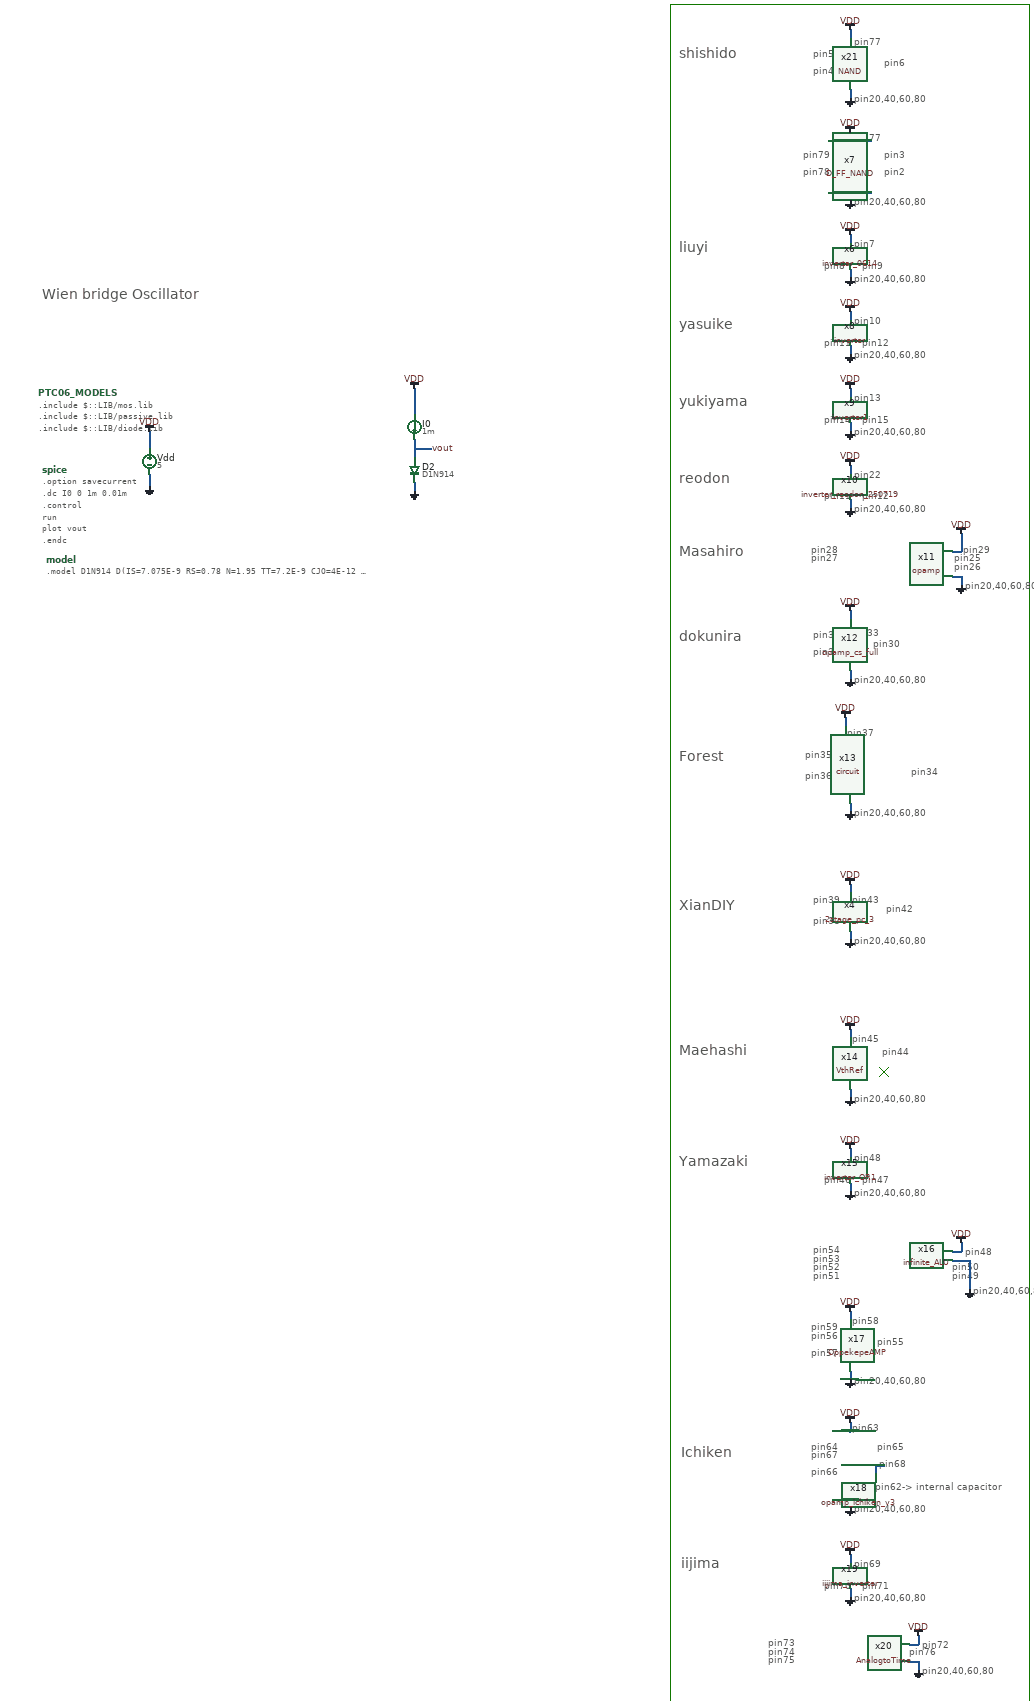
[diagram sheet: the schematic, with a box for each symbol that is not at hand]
v {xschem version=3.4.8RC file_version=1.3}
G {}
K {}
V {}
S {}
F {}
E {}
L 4 1090 1410 1110 1430 {}
L 4 1090 1430 1110 1410 {}
L 4 600 -1080 600 2900 {}
L 4 1440 -1080 1440 2900 {}
L 4 600 -1080 1440 -1080 {}
L 4 600 2900 1440 2900 {}
T {pin8} 960 -480 0 0 0.2 0.2 {}
T {pin9} 1050 -480 0 0 0.2 0.2 {}
T {pin79} 910 -740 0 0 0.2 0.2 {}
T {pin78} 910 -700 0 0 0.2 0.2 {}
T {pin77} 1030 -780 0 0 0.2 0.2 {}
T {pin3} 1100 -740 0 0 0.2 0.2 {}
T {pin2} 1100 -700 0 0 0.2 0.2 {}
T {liuyi} 620 -520 0 0 1 1 {}
T {pin20,40,60,80} 1030 -630 0 0 0.2 0.2 {}
T {pin20,40,60,80} 1030 -450 0 0 0.2 0.2 {}
T {pin7} 1030 -530 0 0 0.2 0.2 {}
T {shishido} 620 -975 0 0 1 1 {}
T {pin20,40,60,80} 1030 -270 0 0 0.2 0.2 {}
T {pin11} 960 -300 0 0 0.2 0.2 {}
T {yasuike} 620 -340 0 0 1 1 {}
T {pin12} 1050 -300 0 0 0.2 0.2 {}
T {pin10} 1030 -350 0 0 0.2 0.2 {}
T {pin20,40,60,80} 1030 -90 0 0 0.2 0.2 {}
T {pin14} 960 -120 0 0 0.2 0.2 {}
T {pin15} 1050 -120 0 0 0.2 0.2 {}
T {pin13} 1030 -170 0 0 0.2 0.2 {}
T {yukiyama} 620 -160 0 0 1 1 {}
T {pin20,40,60,80} 1030 90 0 0 0.2 0.2 {}
T {pin11} 960 60 0 0 0.2 0.2 {}
T {pin12} 1050 60 0 0 0.2 0.2 {}
T {pin22} 1030 10 0 0 0.2 0.2 {}
T {reodon} 620 20 0 0 1 1 {}
T {Masahiro} 620 190 0 0 1 1 {}
T {pin25} 1265 205 0 0 0.2 0.2 {}
T {pin20,40,60,80} 1290 270 0 0 0.2 0.2 {}
T {pin29} 1285 185 0 0 0.2 0.2 {}
T {pin26} 1265 225 0 0 0.2 0.2 {}
T {pin27} 930 205 0 0 0.2 0.2 {}
T {pin28} 930 185 0 0 0.2 0.2 {}
T {pin20,40,60,80} 1030 490 0 0 0.2 0.2 {}
T {pin31} 935 385 0 0 0.2 0.2 {}
T {pin32} 935 425 0 0 0.2 0.2 {}
T {pin30} 1075 405 0 0 0.2 0.2 {}
T {pin33} 1025 380 0 0 0.2 0.2 {}
T {dokunira} 620 390 0 0 1 1 {}
T {Forest} 620 670 0 0 1 1 {}
T {pin20,40,60,80} 1030 800 0 0 0.2 0.2 {}
T {Maehashi} 620 1360 0 0 1 1 {}
T {pin20,40,60,80} 1030 1470 0 0 0.2 0.2 {}
T {pin45} 1025 1330 0 0 0.2 0.2 {}
T {pin44} 1095 1360 0 0 0.2 0.2 {}
T {pin20,40,60,80} 1030 1690 0 0 0.2 0.2 {}
T {pin46} 960 1660 0 0 0.2 0.2 {}
T {pin47} 1050 1660 0 0 0.2 0.2 {}
T {pin48} 1030 1610 0 0 0.2 0.2 {}
T {Yamazaki} 620 1620 0 0 1 1 {}
T {pin20,40,60,80} 1310 1920 0 0 0.2 0.2 {}
T {pin48} 1290 1830 0 0 0.2 0.2 {}
T {pin50} 1260 1865 0 0 0.2 0.2 {}
T {pin49} 1260 1885 0 0 0.2 0.2 {}
T {pin54} 935 1825 0 0 0.2 0.2 {}
T {pin53} 935 1845 0 0 0.2 0.2 {}
T {pin52} 935 1865 0 0 0.2 0.2 {}
T {pin51} 935 1885 0 0 0.2 0.2 {}
T {pin20,40,60,80} 1030 2130 0 0 0.2 0.2 {}
T {pin59} 930 2005 0 0 0.2 0.2 {}
T {pin58} 1025 1990 0 0 0.2 0.2 {}
T {pin55} 1085 2040 0 0 0.2 0.2 {}
T {pin57} 930 2065 0 0 0.2 0.2 {}
T {pin56} 930 2025 0 0 0.2 0.2 {}
T {pin20,40,60,80} 1030 2430 0 0 0.2 0.2 {}
T {* pin62-> internal capacitor} 1060 2380 0 0 0.2 0.2 {}
T {Ichiken} 625 2300 0 0 1 1 {}
T {pin63} 1025 2240 0 0 0.2 0.2 {}
T {pin64} 930 2285 0 0 0.2 0.2 {}
T {pin65} 1085 2285 0 0 0.2 0.2 {}
T {pin67} 930 2305 0 0 0.2 0.2 {}
T {pin66} 930 2345 0 0 0.2 0.2 {}
T {pin68} 1090 2325 0 0 0.2 0.2 {}
T {pin20,40,60,80} 1030 2640 0 0 0.2 0.2 {}
T {pin70} 960 2610 0 0 0.2 0.2 {}
T {pin71} 1050 2610 0 0 0.2 0.2 {}
T {pin69} 1030 2560 0 0 0.2 0.2 {}
T {iijima} 625 2560 0 0 1 1 {}
T {pin20,40,60,80} 1190 2810 0 0 0.2 0.2 {}
T {pin72} 1190 2750 0 0 0.2 0.2 {}
T {pin76} 1160 2765 0 0 0.2 0.2 {}
T {pin73} 830 2745 0 0 0.2 0.2 {}
T {pin74} 830 2765 0 0 0.2 0.2 {}
T {pin75} 830 2785 0 0 0.2 0.2 {}
T {pin20,40,60,80} 1030 -870 0 0 0.2 0.2 {}
T {pin77} 1030 -1005 0 0 0.2 0.2 {}
T {pin5} 935 -975 0 0 0.2 0.2 {}
T {pin4} 935 -935 0 0 0.2 0.2 {}
T {pin6} 1100 -955 0 0 0.2 0.2 {}
T {XianDIY} 620 1020 0 0 1 1 {}
T {Wien bridge Oscillator} -870 -410 0 0 1 1 {}
T {pin34} 1165 705 0 0 0.2 0.2 {}
T {pin35} 915 665 0 0 0.2 0.2 {}
T {pin36} 915 715 0 0 0.2 0.2 {}
T {pin37} 1015 615 0 0 0.2 0.2 {}
T {pin39} 935 1005 0 0 0.2 0.2 {}
T {pin20,40,60,80} 1030 1100 0 0 0.2 0.2 {}
T {pin43} 1025 1005 0 0 0.2 0.2 {}
T {pin38} 935 1055 0 0 0.2 0.2 {}
T {pin42} 1105 1025 0 0 0.2 0.2 {}
N -620 -80 -620 -40 {lab=VDD}
N -620 20 -620 50 {lab=GND}
N 1020 -640 1020 -620 {lab=GND}
N 1020 -780 1020 -760 {lab=VDD}
N 970 -760 1020 -760 {lab=VDD}
N 1020 -760 1070 -760 {lab=VDD}
N 970 -640 1020 -640 {lab=GND}
N 1020 -640 1070 -640 {lab=GND}
N 1020 -460 1020 -440 {lab=GND}
N 1020 -540 1020 -520 {lab=VDD}
N 1020 -280 1020 -260 {lab=GND}
N 1020 -360 1020 -340 {lab=VDD}
N 1020 -100 1020 -80 {lab=GND}
N 1020 -180 1020 -160 {lab=VDD}
N 1020 80 1020 100 {lab=GND}
N 1020 0 1020 20 {lab=VDD}
N 1280 160 1280 200 {lab=VDD}
N 1260 200 1280 200 {lab=VDD}
N 1280 260 1280 280 {lab=GND}
N 1260 260 1280 260 {lab=GND}
N 1020 480 1020 500 {lab=GND}
N 1020 340 1020 360 {lab=VDD}
N 1010 590 1010 610 {lab=VDD}
N 1020 790 1020 810 {lab=GND}
N 1020 1460 1020 1480 {lab=GND}
N 1020 1320 1020 1340 {lab=VDD}
N 1020 1680 1020 1700 {lab=GND}
N 1020 1600 1020 1620 {lab=VDD}
N 1280 1820 1280 1840 {lab=VDD}
N 1260 1840 1280 1840 {lab=VDD}
N 1260 1860 1300 1860 {lab=GND}
N 1300 1860 1300 1930 {lab=GND}
N 1020 2120 1020 2140 {lab=GND}
N 1035 2140 1040 2140 {lab=#net1}
N 1020 2420 1020 2440 {lab=GND}
N 980 2420 1020 2420 {lab=GND}
N 1020 2420 1040 2420 {lab=GND}
N 1020 2240 1020 2260 {lab=VDD}
N 980 2260 1020 2260 {lab=VDD}
N 1020 2260 1040 2260 {lab=VDD}
N 1080 2340 1080 2360 {lab=#net2}
N 1080 2340 1100 2340 {lab=#net2}
N 1020 2630 1020 2650 {lab=GND}
N 1020 2550 1020 2570 {lab=VDD}
N 1160 2800 1180 2800 {lab=GND}
N 1180 2800 1180 2820 {lab=GND}
N 1180 2740 1180 2760 {lab=VDD}
N 1160 2760 1180 2760 {lab=VDD}
N 1020 -1020 1020 -1000 {lab=VDD}
N 1020 1980 1020 2000 {lab=VDD}
N 1020 -880 1020 -860 {lab=GND}
N 1020 1090 1020 1110 {lab=GND}
N 1020 980 1020 1000 {lab=VDD}
N 0 40 0 60 {lab=GND}
N 0 -180 0 -160 {lab=VDD}
N 0 -60 0 -20 {lab=vout}
N 0 -40 40 -40 {lab=vout}
N 0 -160 0 -120 {lab=VDD}
C {devices/code.sym} -880 -170 0 0 {name=PTC06_MODELS
only_toplevel=true
format="tcleval( @value )"
value=".include $::LIB/mos.lib
.include $::LIB/passive.lib
.include $::LIB/diode.lib"
spice_ignore=false}
C {devices/code_shown.sym} -870 10 0 0 {name=spice only_toplevel=false value="
.option savecurrent
.dc I0 0 1m 0.01m
.control
run
plot vout
.endc
"}
C {devices/vsource.sym} -620 -10 0 0 {name=Vdd value=5 savecurrent=false}
C {devices/vdd.sym} -620 -80 0 0 {name=l4 lab=VDD}
C {devices/gnd.sym} -620 50 0 0 {name=l5 lab=GND}
C {../sanken/liuyi/invertar_0614.sym} 1020 -490 0 0 {name=x6}
C {../sanken/shishido/D_FF_NAND/D_FF_NAND.sym} 1020 -700 0 0 {name=x7}
C {devices/gnd.sym} 1020 -620 0 0 {name=l17 lab=GND}
C {devices/vdd.sym} 1020 -540 0 0 {name=l19 lab=VDD}
C {devices/gnd.sym} 1020 -440 0 0 {name=l20 lab=GND}
C {../sanken/yasuike/inverter/inverter.sym} 1020 -310 0 0 {name=x8}
C {devices/gnd.sym} 1020 -260 0 0 {name=l21 lab=GND}
C {devices/vdd.sym} 1020 -360 0 0 {name=l22 lab=VDD}
C {devices/vdd.sym} 1020 -780 0 0 {name=l23 lab=VDD}
C {../sanken/yukiyama/inverter1.sym} 1020 -130 0 0 {name=x9}
C {devices/gnd.sym} 1020 -80 0 0 {name=l18 lab=GND}
C {devices/vdd.sym} 1020 -180 0 0 {name=l24 lab=VDD}
C {../reodon/inverter_reodon_250719.sym} 1020 50 0 0 {name=x10}
C {devices/gnd.sym} 1020 100 0 0 {name=l25 lab=GND}
C {devices/vdd.sym} 1020 0 0 0 {name=l26 lab=VDD}
C {../GroupWork/Team_masahiro/opamp.sym} 1110 230 0 0 {name=x11}
C {devices/vdd.sym} 1280 160 0 0 {name=l27 lab=VDD}
C {devices/gnd.sym} 1280 280 0 0 {name=l28 lab=GND}
C {../GroupWork/Team_Ando/dokunira/sch/opamp_cs_full.sym} 980 420 0 0 {name=x12}
C {devices/gnd.sym} 1020 500 0 0 {name=l29 lab=GND}
C {devices/vdd.sym} 1020 340 0 0 {name=l30 lab=VDD}
C {../GroupWork/Team_Ando/foorests/circuit.sym} 1090 760 0 0 {name=x13}
C {devices/vdd.sym} 1010 590 0 0 {name=l31 lab=VDD}
C {devices/gnd.sym} 1020 810 0 0 {name=l32 lab=GND}
C {../GroupWork/Team_Ando/YuMaehashi/sch/VthRef.sym} 1040 1400 0 0 {name=x14}
C {devices/gnd.sym} 1020 1480 0 0 {name=l33 lab=GND}
C {devices/vdd.sym} 1020 1320 0 0 {name=l34 lab=VDD}
C {../sanken/yamazaki/inverter_OR1/inverter_OR1.sym} 1020 1650 0 0 {name=x15}
C {devices/gnd.sym} 1020 1700 0 0 {name=l35 lab=GND}
C {devices/vdd.sym} 1020 1600 0 0 {name=l36 lab=VDD}
C {../sanken/yamazaki/infinite_ALU/infinite_ALU.sym} 1110 1870 0 0 {name=x16}
C {devices/vdd.sym} 1280 1820 0 0 {name=l37 lab=VDD}
C {devices/gnd.sym} 1300 1930 0 0 {name=l38 lab=GND}
C {../sanken/yamazaki/OppekepeAMP/OppekepeAMP.sym} 1020 2060 0 0 {name=x17}
C {devices/gnd.sym} 1020 2140 0 0 {name=l39 lab=GND}
C {devices/vdd.sym} 1020 1980 0 0 {name=l40 lab=VDD}
C {../GroupWork/Team_ichiken/opamp_ichiken_v3.sym} 1020 2340 0 0 {name=x18}
C {devices/gnd.sym} 1020 2440 0 0 {name=l41 lab=GND}
C {devices/vdd.sym} 1020 2240 0 0 {name=l42 lab=VDD}
C {../sanken/iijima/inverter/iijima_inverter.sym} 1020 2600 0 0 {name=x19}
C {devices/gnd.sym} 1020 2650 0 0 {name=l43 lab=GND}
C {devices/vdd.sym} 1020 2550 0 0 {name=l44 lab=VDD}
C {../sanken/iijima/AnalogtoTime/AnalogtoTime.sym} 1010 2780 0 0 {name=x20}
C {devices/gnd.sym} 1180 2820 0 0 {name=l45 lab=GND}
C {devices/vdd.sym} 1180 2740 0 0 {name=l46 lab=VDD}
C {../sanken/shishido/NAND/NAND.sym} 1020 -940 0 0 {name=x21}
C {devices/gnd.sym} 1020 -860 0 0 {name=l47 lab=GND}
C {devices/vdd.sym} 1020 -1020 0 0 {name=l48 lab=VDD}
C {/home/yutaka/01_proj/04_ptc06-02/ISHI-KAI_Multiple_Projects_OpenMPW_PTC06-2/member_project/GroupWork/Team_Ando/ugeugeHigh/2stage_pc_3.sym} 1090 1040 0 0 {name=x4}
C {devices/gnd.sym} 1020 1110 0 0 {name=l9 lab=GND}
C {devices/vdd.sym} 1020 980 0 0 {name=l11 lab=VDD}
C {devices/diode.sym} 0 10 0 0 {name=D2 model=D1N914 area=1}
C {devices/code_shown.sym} -860 220 0 0 {name=model only_toplevel=false value="
.model D1N914 D(IS=7.075E-9 RS=0.78 N=1.95 TT=7.2E-9 CJO=4E-12 VJ=0.657 M=0.4 BV=100 IBV=0.0001 )
"}
C {devices/vdd.sym} 0 -180 0 0 {name=l3 lab=VDD}
C {devices/gnd.sym} 0 60 0 0 {name=l6 lab=GND}
C {devices/lab_wire.sym} 40 -40 0 1 {name=p1 sig_type=std_logic lab=vout}
C {devices/isource.sym} 0 -90 0 0 {name=I0 value=1m}
